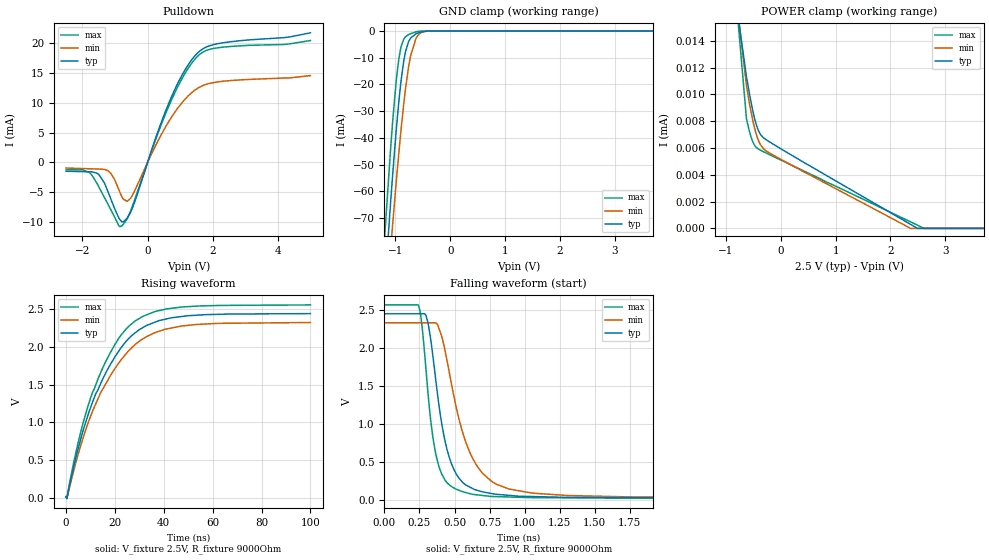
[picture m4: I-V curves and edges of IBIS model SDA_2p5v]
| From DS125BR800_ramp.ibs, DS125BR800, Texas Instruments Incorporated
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[Model]   SDA_2p5v
Model_type   Open_drain
Polarity   Non-Inverting
Vmeas = 1.25
Vref = 2.5
Cref = 1pF
Rref = 9000
|   typ   min   max
C_comp   1.027pF   0.945pF   1.110pF
[Voltage Range]   2.5   2.375   2.625
[Temperature Range]   25   105   -40
[Pullup Reference]   2.5   2.375   2.625
[Pulldown Reference]   0   0   0
[Power Clamp Reference]   2.5   2.375   2.625
[GND Clamp Reference]   0   0   0
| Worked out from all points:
|   slope of the pulldown table from 0 to 0.375 V, typ, clamps not added: 61.9 ohm
|   GND clamp passes 1 mA (typ) near -0.62 V on its own axis
|   POWER clamp passes 1 mA (typ) near -1.62 V on its own axis
|   falling waveform, V_fixture 2.5V, R_fixture 9000Ohm: 20-80 % time 132ps typ, 205ps min, 95.9ps max; typ from 2.45 V to 0.016 V
|   rising waveform, V_fixture 2.5V, R_fixture 9000Ohm: 20-80 % time 18ns typ, 19.3ns min, 16.8ns max; typ from 0.016 V to 2.44 V
[Pulldown]
|   Voltage   I(typ)   I(min)   I(max)
-2.5V     -1.481mA   -951.1uA   -1.198mA
-1.788V   -1.585mA   -1.071mA   -1.691mA
-1.495V   -2.031mA   -1.121mA   -4.116mA
-1.127V   -6.146mA   -1.834mA   -7.953mA
-790mV    -9.966mA   -5.747mA   -10.67mA
-625mV    -9.376mA   -6.543mA   -9.476mA
-497.5mV  -8.106mA   -5.819mA   -7.83mA
740mV     11.11mA    7.659mA    10.58mA
1.16V     15.68mA    10.7mA     15.09mA
1.542V    18.45mA    12.48mA    17.89mA
2.21V     20.01mA    13.58mA    19.31mA
4.992V    21.78mA    14.59mA    20.49mA
[GND Clamp]
|   Voltage   I(typ)   I(min)   I(max)
-2.5V     -514.6mA   -477.8mA   -525.7mA
-1.202V   -98.1mA    -112.2mA   -79.36mA
-1.083V   -63.05mA   -80.82mA   -43.05mA
-1.052V   -54.8mA    -73.25mA   -34.88mA
-985mV    -37.45mA   -56.81mA   -18.93mA
-932.5mV  -25.63mA   -44.79mA   -9.987mA
-850mV    -11.66mA   -27.85mA   -3.192mA
-760mV    -4.02mA    -13.57mA   -1.357mA
-722.5mV  -2.638mA   -9.319mA   -1.004mA
-625mV    -1.076mA   -2.819mA   -314.7uA
-437.5mV  -70.57uA   -112.2uA   -1.922uA
4.992V    0A         0A         0A
[POWER Clamp]
|   Voltage   I(typ)   I(min)   I(max)
-2.5V     9.236mA    5.527mA    13.5mA
-1.173V   27.37uA    30uA       34.24uA
-625mV    11.34uA    10.66uA    8.178uA
-572.5mV  10.1uA     9.379uA    7.274uA
-527.5mV  9.139uA    8.412uA    6.663uA
-445mV    7.734uA    7.016uA    6.049uA
-362.5mV  6.977uA    6.199uA    5.821uA
-205mV    6.459uA    5.626uA    5.507uA
2.36V     315.3nA    0A         499.5nA
2.487V    0A         0A         250.7nA
2.607V    0A         0A         0A
4.992V    0A         0A         0A
[Ramp]
R_load = 9000
|   typ   min   max
dV/dt_r   1.45395/1.80469e-08   1.38003/1.92593e-08   1.52443/1.68152e-08
dV/dt_f   1.45782/1.31784e-10   1.38335/2.05093e-10   1.52929/9.58521e-11
[Falling Waveform]
V_fixture = 2.5V
V_fixture_min = 2.375V
V_fixture_max = 2.625V
R_fixture = 9000Ohm
C_fixture = 0F
|   Time   V(typ)   V(min)   V(max)
0s        2.446V     2.327V     2.562V
246.2ps   2.446V     2.328V     2.544V
295.4ps   2.428V     2.328V     1.74V
346.2ps   1.885V     2.328V     818.9mV
379.5ps   1.378V     2.304V     502.4mV
432.8ps   769.9mV    1.958V     256.3mV
553.4ps   236.3mV    912.8mV    108.7mV
656.2ps   126.6mV    456.5mV    64.78mV
1.025ns   43.17mV    96.46mV    28.17mV
100ns     16.01mV    21.7mV     13.48mV
[Rising Waveform]
V_fixture = 2.5V
V_fixture_min = 2.375V
V_fixture_max = 2.625V
R_fixture = 9000Ohm
C_fixture = 0F
|   Time   V(typ)   V(min)   V(max)
0s        16.01mV    21.68mV    13.47mV
443.4ps   11.51mV    4.442mV    18.65mV
3.133ns   414.5mV    359.9mV    471.2mV
6.018ns   781.2mV    696.7mV    875.3mV
10.92ns   1.276V     1.156V     1.406V
19.94ns   1.864V     1.71V      2.029V
28.48ns   2.19V      2.036V     2.346V
36.81ns   2.331V     2.193V     2.47V
47.28ns   2.401V     2.275V     2.526V
100ns     2.439V     2.322V     2.554V
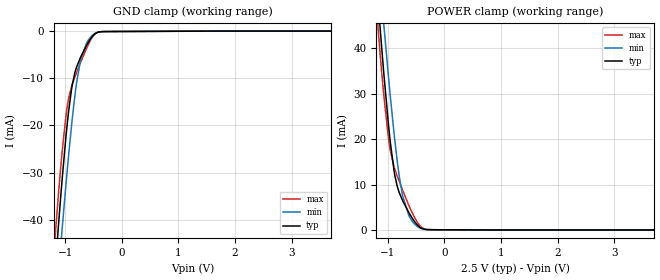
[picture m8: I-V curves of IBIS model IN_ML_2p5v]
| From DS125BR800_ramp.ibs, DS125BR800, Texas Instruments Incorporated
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[Model]   IN_ML_2p5v
Model_type   Input
Vinl = 0.8
Vinh = 2
|   typ   min   max
C_comp   1.378pF   1.280pF   1.479p
[Voltage Range]   2.5   2.375   2.625
[Temperature Range]   25   105   -40
[Power Clamp Reference]   2.5   2.375   2.625
[GND Clamp Reference]   0   0   0
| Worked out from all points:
|   GND clamp passes 1 mA (typ) near -0.51 V on its own axis
|   POWER clamp passes 1 mA (typ) near -0.47 V on its own axis
[GND Clamp]
|   Voltage   I(typ)   I(min)   I(max)
-2.5V     -295.8mA   -278.1mA   -317.3mA
-1.173V   -49.97mA   -59.56mA   -43.03mA
-1.113V   -40.38mA   -50.57mA   -33.69mA
-1.052V   -31.35mA   -41.84mA   -25.49mA
-985mV    -22.26mA   -32.44mA   -17.91mA
-940mV    -17.12mA   -26.52mA   -14.36mA
-872.5mV  -11.29mA   -18.38mA   -11.24mA
-797.5mV  -7.614mA   -10.93mA   -8.788mA
-730mV    -5.613mA   -6.282mA   -6.733mA
-625mV    -3.1mA     -2.616mA   -3.745mA
-460mV    -474.4uA   -411.4uA   -474.7uA
4.992V    0A         0A         0A
[POWER Clamp]
|   Voltage   I(typ)   I(min)   I(max)
-2.5V     296.6mA    279.9mA    317.4mA
-1.188V   53.28mA    62.9mA     47.28mA
-1.127V   43.64mA    53.93mA    37.98mA
-1.067V   34.47mA    45.2mA     29.62mA
-985mV    23.13mA    33.71mA    20.14mA
-887.5mV  13.07mA    21.36mA    14mA
-797.5mV  8.306mA    12.04mA    10.78mA
-737.5mV  6.519mA    7.594mA    8.815mA
-625mV    3.821mA    3.132mA    5.399mA
-430mV    605.3uA    423.3uA    953.5uA
-205mV    53.58uA    52.79uA    54.27uA
4.992V    0A         0A         0A
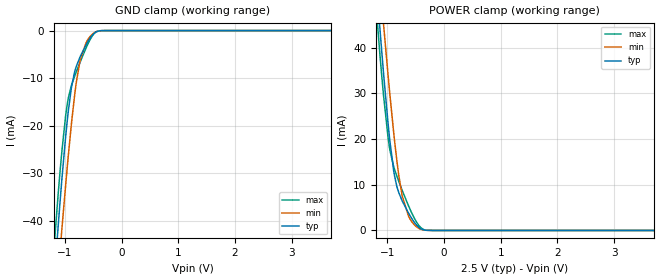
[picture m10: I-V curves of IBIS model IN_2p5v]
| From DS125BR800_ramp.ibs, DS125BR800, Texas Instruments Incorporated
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[Model]   IN_2p5v
Model_type   Input
Vinl = 0.8
Vinh = 2
|   typ   min   max
C_comp   1.378pF   1.280pF   1.479p
[Voltage Range]   2.5   2.375   2.625
[Temperature Range]   25   105   -40
[Power Clamp Reference]   2.5   2.375   2.625
[GND Clamp Reference]   0   0   -0
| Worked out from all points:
|   GND clamp passes 1 mA (typ) near -0.52 V on its own axis
|   POWER clamp passes 1 mA (typ) near -0.47 V on its own axis
[GND Clamp]
|   Voltage   I(typ)   I(min)   I(max)
-2.5V     -295.6mA   -277.9mA   -317.2mA
-1.173V   -49.86mA   -59.47mA   -42.92mA
-1.113V   -40.27mA   -50.48mA   -33.58mA
-1.052V   -31.25mA   -41.75mA   -25.37mA
-985mV    -22.15mA   -32.35mA   -17.8mA
-940mV    -17.01mA   -26.43mA   -14.24mA
-880mV    -11.71mA   -19.14mA   -11.39mA
-797.5mV  -7.502mA   -10.83mA   -8.669mA
-730mV    -5.502mA   -6.186mA   -6.616mA
-625mV    -2.992mA   -2.519mA   -3.632mA
-460mV    -370.9uA   -318.5uA   -365.4uA
4.992V    0A         0A         0A
[POWER Clamp]
|   Voltage   I(typ)   I(min)   I(max)
-2.5V     296.5mA    279.8mA    317.4mA
-1.188V   53.22mA    62.84mA    47.22mA
-1.127V   43.58mA    53.88mA    37.92mA
-1.067V   34.41mA    45.14mA    29.56mA
-985mV    23.07mA    33.66mA    20.07mA
-887.5mV  13.01mA    21.3mA     13.93mA
-797.5mV  8.242mA    11.98mA    10.72mA
-737.5mV  6.456mA    7.535mA    8.753mA
-625mV    3.761mA    3.073mA    5.339mA
-437.5mV  620.2uA    414.9uA    1.009mA
-205mV    7.977uA    8.283uA    8.505uA
4.992V    0A         0A         0A
